# This file is work-product from a Cadence Design Systems tool run at UCLA by NanoCAD students (Richard Chen and Jooyeon Jeong) under an academic end-user license agreement. 
# We thank Cadence Design Systems for permission to share this tool work-product publicly in GitHub.

# -------------------------------
# Generated by:    Cadence Innovus 21.18-s099_1
# OS:              Linux x86_64
# Command:         write_lef_abstract 
# -------------------------------

# 09-01-2026: Changed the CLASS from BLOCK to PAD

VERSION 5.8 ;

BUSBITCHARS "[]" ;
DIVIDERCHAR "/" ;

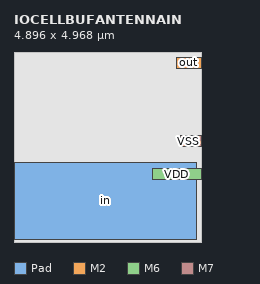
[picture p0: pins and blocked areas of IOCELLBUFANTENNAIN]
MACRO IOCELLBUFANTENNAIN
  CLASS PAD ;
  SIZE 4.896000 BY 4.968000 ;
  FOREIGN IOCELLBUFANTENNAIN 0.000000 0.000000 ;
  ORIGIN 0 0 ;
  SYMMETRY X Y R90 ;
  PIN in
    DIRECTION INPUT ;
    USE SIGNAL ;
    PORT
      LAYER Pad ;
        RECT 0.000000 0.076000 4.771000 2.076000 ;
    END
  END in
  PIN out
    DIRECTION OUTPUT ;
    USE SIGNAL ;
    PORT
      LAYER M2 ;
        RECT 4.246000 4.545000 4.896000 4.833000 ;
    END
  END out
  PIN VDD
    DIRECTION INOUT ;
    USE POWER ;
    PORT
      LAYER M6 ;
        RECT 3.615000 1.632000 4.896000 1.920000 ;
    END
  END VDD
  PIN VSS
    DIRECTION INOUT ;
    USE GROUND ;
    PORT
      LAYER M7 ;
        RECT 4.352000 2.496000 4.896000 2.784000 ;
    END
  END VSS
  OBS
    LAYER M1 ;
      RECT 0.000000 0.000000 4.896000 4.968000 ;
    LAYER M2 ;
      RECT 0.000000 4.851000 4.896000 4.968000 ;
      RECT 0.000000 4.527000 4.228000 4.851000 ;
      RECT 0.000000 0.000000 4.896000 4.527000 ;
    LAYER M3 ;
      RECT 0.000000 0.000000 4.896000 4.968000 ;
    LAYER M4 ;
      RECT 0.000000 0.000000 4.896000 4.968000 ;
    LAYER M5 ;
      RECT 0.000000 0.000000 4.896000 4.968000 ;
    LAYER M6 ;
      RECT 0.000000 1.992000 4.896000 4.968000 ;
      RECT 0.000000 1.560000 3.543000 1.992000 ;
      RECT 0.000000 0.000000 4.896000 1.560000 ;
    LAYER M7 ;
      RECT 0.000000 2.856000 4.896000 4.968000 ;
      RECT 0.000000 2.424000 4.280000 2.856000 ;
      RECT 0.000000 0.000000 4.896000 2.424000 ;
    LAYER M8 ;
      RECT 0.000000 0.000000 4.896000 4.968000 ;
    LAYER M9 ;
      RECT 0.000000 0.000000 4.896000 4.968000 ;
  END
END IOCELLBUFANTENNAIN

END LIBRARY
